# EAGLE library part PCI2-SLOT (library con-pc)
PCI BOARD SHORT

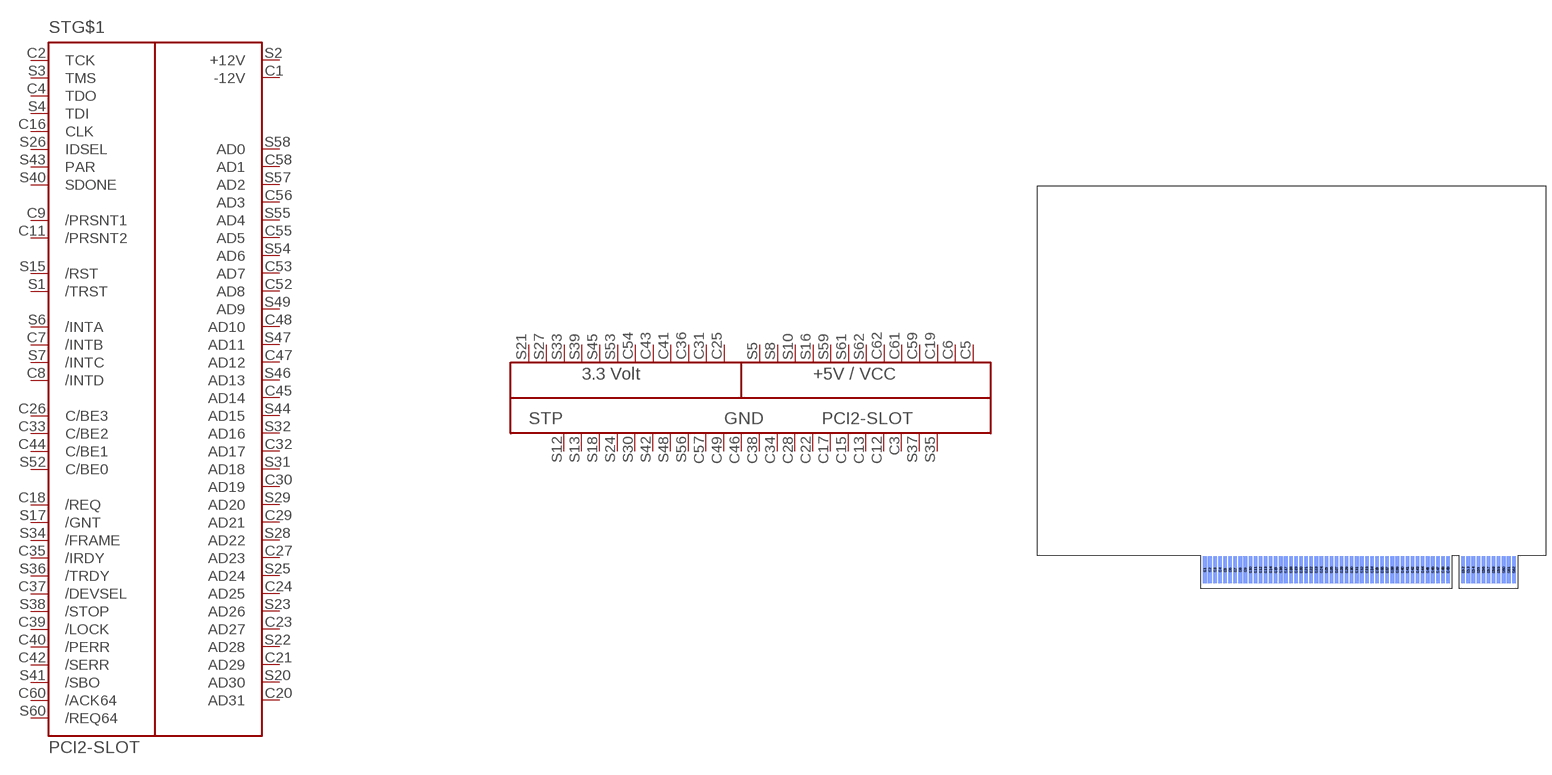
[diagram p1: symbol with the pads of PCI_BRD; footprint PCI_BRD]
Designator prefix ST; gates G$1=PCI2_CON P=PCI_PWR

## PCI2-SLOT  [PCI_BRD]
C1  G$1:-12V  pwr
C2  G$1:TCK  pas
C3  P:GND  pwr
C4  G$1:TDO  pas
C5  P:+5V  pwr
C6  P:+5V  pwr
C7  G$1:/INTB  pas
C8  G$1:/INTD  pas
C9  G$1:/PRSNT1  pas
C10  P:NC3  nc
C11  G$1:/PRSNT2  pas
C12  P:GND  pwr
C13  P:GND  pwr
C14  P:NC4  nc
C15  P:GND  pwr
C16  G$1:CLK  pas
C17  P:GND  pwr
C18  G$1:/REQ  pas
C19  P:+5V  pwr
C20  G$1:AD31  pas
C21  G$1:AD29  pas
C22  P:GND  pwr
C23  G$1:AD27  pas
C24  G$1:AD25  pas
C25  P:+3,3V  pwr
C26  G$1:C/BE3  pas
C27  G$1:AD23  pas
C28  P:GND  pwr
C29  G$1:AD21  pas
C30  G$1:AD19  pas
C31  P:+3,3V  pwr
C32  G$1:AD17  pas
C33  G$1:C/BE2  pas
C34  P:GND  pwr
C35  G$1:/IRDY  pas
C36  P:+3,3V  pwr
C37  G$1:/DEVSEL  pas
C38  P:GND  pwr
C39  G$1:/LOCK  pas
C40  G$1:/PERR  pas
C41  P:+3,3V  pwr
C42  G$1:/SERR  pas
C43  P:+3,3V  pwr
C44  G$1:C/BE1  pas
C45  G$1:AD14  pas
C46  P:GND  pwr
C47  G$1:AD12  pas
C48  G$1:AD10  pas
C49  P:GND  pwr
C52  G$1:AD8  pas
C53  G$1:AD7  pas
C54  P:+3,3V  pwr
C55  G$1:AD5  pas
C56  G$1:AD3  pas
C57  P:GND  pwr
C58  G$1:AD1  pas
C59  P:+5V  pwr
C60  G$1:/ACK64  pas
C61  P:+5V  pwr
C62  P:+5V  pwr
S1  G$1:/TRST  pas
S2  G$1:+12V  pwr
S3  G$1:TMS  pas
S4  G$1:TDI  pas
S5  P:+5V  pwr
S6  G$1:/INTA  pas
S7  G$1:/INTC  pas
S8  P:+5V  pwr
S9  P:NC0  nc
S10  P:+5V  pwr
S11  P:NC5  nc
S12  P:GND  pwr
S13  P:GND  pwr
S14  P:NC1  nc
S15  G$1:/RST  pas
S16  P:+5V  pwr
S17  G$1:/GNT  pas
S18  P:GND  pwr
S19  P:NC2  nc
S20  G$1:AD30  pas
S21  P:+3,3V  pwr
S22  G$1:AD28  pas
S23  G$1:AD26  pas
S24  P:GND  pwr
S25  G$1:AD24  pas
S26  G$1:IDSEL  pas
S27  P:+3,3V  pwr
S28  G$1:AD22  pas
S29  G$1:AD20  pas
S30  P:GND  pwr
S31  G$1:AD18  pas
S32  G$1:AD16  pas
S33  P:+3,3V  pwr
S34  G$1:/FRAME  pas
S35  P:GND  pas
S36  G$1:/TRDY  pas
S37  P:GND  pwr
S38  G$1:/STOP  pas
S39  P:+3,3V  pas
S40  G$1:SDONE  pas
S41  G$1:/SBO  pas
S42  P:GND  pwr
S43  G$1:PAR  pas
S44  G$1:AD15  pas
S45  P:+3,3V  pwr
S46  G$1:AD13  pas
S47  G$1:AD11  pas
S48  P:GND  pwr
S49  G$1:AD9  pas
S52  G$1:C/BE0  pas
S53  P:+3,3V  pwr
S54  G$1:AD6  pas
S55  G$1:AD4  pas
S56  P:GND  pwr
S57  G$1:AD2  pas
S58  G$1:AD0  pas
S59  P:+5V  pwr
S60  G$1:/REQ64  pas
S61  P:+5V  pwr
S62  P:+5V  pwr

## Footprint PCI_BRD (pad centres in mm)
PCI BOARD SHORT
smd 0.91 x 6.7: C1 41.91,4.763; C2 43.18,4.763; C3 44.45,4.763; C4 45.72,4.763; C5 46.99,4.763; C6 48.26,4.763; C7 49.53,4.763; C8 50.8,4.763; C9 52.07,4.763; C10 53.34,4.763; C11 54.61,4.763; C12 55.88,4.763; C13 57.15,4.763; C14 58.42,4.763; C15 59.69,4.763; C16 60.96,4.763; C17 62.23,4.763; C18 63.5,4.763; C19 64.77,4.763; C20 66.04,4.763; C21 67.31,4.763; C22 68.58,4.763; C23 69.85,4.763; C24 71.12,4.763; C25 72.39,4.763; C26 73.66,4.763; C27 74.93,4.763; C28 76.2,4.763; C29 77.47,4.763; C30 78.74,4.763; C31 80.01,4.763; C32 81.28,4.763; C33 82.55,4.763; C34 83.82,4.763; C35 85.09,4.763; C36 86.36,4.763; C37 87.63,4.763; C38 88.9,4.763; C39 90.17,4.763; C40 91.44,4.763; C41 92.71,4.763; C42 93.98,4.763; C43 95.25,4.763; C44 96.52,4.763; C45 97.79,4.763; C46 99.06,4.763; C47 100.33,4.763; C48 101.6,4.763; C49 102.87,4.763; C52 106.68,4.763; C53 107.95,4.763; C54 109.22,4.763; C55 110.49,4.763; C56 111.76,4.763; C57 113.03,4.763; C58 114.3,4.763; C59 115.57,4.763; C60 116.84,4.763; C61 118.11,4.763; C62 119.38,4.763
smd 0.91 x 6.7 bottom: S1 41.91,4.763; S2 43.18,4.763; S3 44.45,4.763; S4 45.72,4.763; S5 46.99,4.763; S6 48.26,4.763; S7 49.53,4.763; S8 50.8,4.763; S9 52.07,4.763; S10 53.34,4.763; S11 54.61,4.763; S12 55.88,4.763; S13 57.15,4.763; S14 58.42,4.763; S15 59.69,4.763; S16 60.96,4.763; S17 62.23,4.763; S18 63.5,4.763; S19 64.77,4.763; S20 66.04,4.763; S21 67.31,4.763; S22 68.58,4.763; S23 69.85,4.763; S24 71.12,4.763; S25 72.39,4.763; S26 73.66,4.763; S27 74.93,4.763; S28 76.2,4.763; S29 77.47,4.763; S30 78.74,4.763; S31 80.01,4.763; S32 81.28,4.763; S33 82.55,4.763; S34 83.82,4.763; S35 85.09,4.763; S36 86.36,4.763; S37 87.63,4.763; S38 88.9,4.763; S39 90.17,4.763; S40 91.44,4.763; S41 92.71,4.763; S42 93.98,4.763; S43 95.25,4.763; S44 96.52,4.763; S45 97.79,4.763; S46 99.06,4.763; S47 100.33,4.763; S48 101.6,4.763; S49 102.87,4.763; S52 106.68,4.763; S53 107.95,4.763; S54 109.22,4.763; S55 110.49,4.763; S56 111.76,4.763; S57 113.03,4.763; S58 114.3,4.763; S59 115.57,4.763; S60 116.84,4.763; S61 118.11,4.763; S62 119.38,4.763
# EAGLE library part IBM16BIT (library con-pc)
16-bit CARD IBM/PC-AT

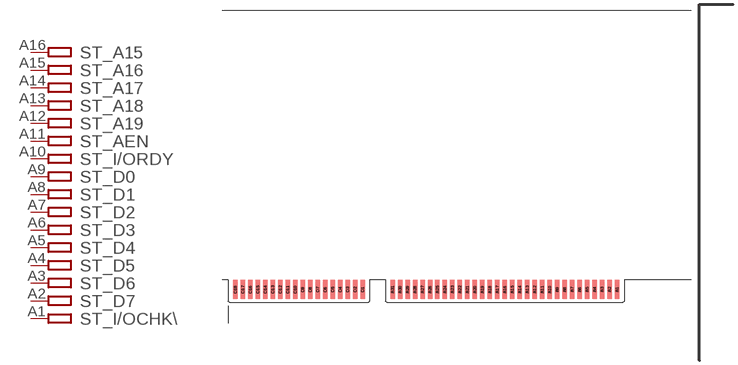
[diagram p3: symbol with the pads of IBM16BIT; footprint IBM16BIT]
Designator prefix ST; gates _I/OCHK\=ATPIN _D7=ATPIN _D6=ATPIN _D5=ATPIN _D4=ATPIN _D3=ATPIN _D2=ATPIN _D1=ATPIN _D0=ATPIN _I/ORDY=ATPIN _AEN=ATPIN _A19=ATPIN _A18=ATPIN _A17=ATPIN _A16=ATPIN _A15=ATPIN _A14=ATPIN _A13=ATPIN _A12=ATPIN _A11=ATPIN _A10=ATPIN _A9=ATPIN _A8=ATPIN _A7=ATPIN _A6=ATPIN _A5=ATPIN _A4=ATPIN _A3=ATPIN _A2=ATPIN _A1=ATPIN _A0=ATPIN _GND@3=ATPIN _RESET=ATPIN _+5V@2=ATPIN _IRQ9=ATPIN _-5V=ATPIN _DRQ2=ATPIN _-12V=ATPIN _CARDS=ATPIN _+12V=ATPIN _GND@2=ATPIN _MEMW\=ATPIN _MEMR\=ATPIN _IOW\=ATPIN _IOR\=ATPIN _DACK3\=ATPIN _DRQ3=ATPIN _DACK1\=ATPIN _DRQ1=ATPIN _REFRS=ATPIN _CLK=ATPIN _IRQ7=ATPIN _IRQ6=ATPIN _IRQ5=ATPIN _IRQ4=ATPIN _IRQ3=ATPIN _DACK2\=ATPIN _T/C=ATPIN _ALE=ATPIN _+5V@1=ATPIN _OSC=ATPIN _GND@1=ATPIN _SBHE=ATPIN _LA23=ATPIN _LA22=ATPIN _LA21=ATPIN _LA20=ATPIN _LA19=ATPIN _LA18=ATPIN _LA17=ATPIN _MEM_R=ATPIN _MEM_W=ATPIN _D8=ATPIN _D9=ATPIN _D10=ATPIN _D11=ATPIN _D12=ATPIN _D13=ATPIN _D14=ATPIN _D15=ATPIN _MEMCS16=ATPIN _I/OCS16=ATPIN _IRQ10=ATPIN _IRQ11=ATPIN _IRQ12=ATPIN _IRQ15=ATPIN _IRQ14=ATPIN _DACK0=ATPIN _DRQ0=ATPIN _DACK5=ATPIN _DRQ5=ATPIN _DACK6=ATPIN _DRQ6=ATPIN _DACK7=ATPIN _DRQ7=ATPIN _+5V@3=ATPIN _MASTER=ATPIN _GND@4=ATPIN

## IBM16BIT  [IBM16BIT]
A1  _I/OCHK\:P
A2  _D7:P
A3  _D6:P
A4  _D5:P
A5  _D4:P
A6  _D3:P
A7  _D2:P
A8  _D1:P
A9  _D0:P
A10  _I/ORDY:P
A11  _AEN:P
A12  _A19:P
A13  _A18:P
A14  _A17:P
A15  _A16:P
A16  _A15:P
A17  _A14:P
A18  _A13:P
A19  _A12:P
A20  _A11:P
A21  _A10:P
A22  _A9:P
A23  _A8:P
A24  _A7:P
A25  _A6:P
A26  _A5:P
A27  _A4:P
A28  _A3:P
A29  _A2:P
A30  _A1:P
A31  _A0:P
B1  _GND@3:P
B2  _RESET:P
B3  _+5V@2:P
B4  _IRQ9:P
B5  _-5V:P
B6  _DRQ2:P
B7  _-12V:P
B8  _CARDS:P
B9  _+12V:P
B10  _GND@2:P
B11  _MEMW\:P
B12  _MEMR\:P
B13  _IOW\:P
B14  _IOR\:P
B15  _DACK3\:P
B16  _DRQ3:P
B17  _DACK1\:P
B18  _DRQ1:P
B19  _REFRS:P
B20  _CLK:P
B21  _IRQ7:P
B22  _IRQ6:P
B23  _IRQ5:P
B24  _IRQ4:P
B25  _IRQ3:P
B26  _DACK2\:P
B27  _T/C:P
B28  _ALE:P
B29  _+5V@1:P
B30  _OSC:P
B31  _GND@1:P
C1  _SBHE:P
C2  _LA23:P
C3  _LA22:P
C4  _LA21:P
C5  _LA20:P
C6  _LA19:P
C7  _LA18:P
C8  _LA17:P
C9  _MEM_R:P
C10  _MEM_W:P
C11  _D8:P
C12  _D9:P
C13  _D10:P
C14  _D11:P
C15  _D12:P
C16  _D13:P
C17  _D14:P
C18  _D15:P
D1  _MEMCS16:P
D2  _I/OCS16:P
D3  _IRQ10:P
D4  _IRQ11:P
D5  _IRQ12:P
D6  _IRQ15:P
D7  _IRQ14:P
D8  _DACK0:P
D9  _DRQ0:P
D10  _DACK5:P
D11  _DRQ5:P
D12  _DACK6:P
D13  _DRQ6:P
D14  _DACK7:P
D15  _DRQ7:P
D16  _+5V@3:P
D17  _MASTER:P
D18  _GND@4:P

## Footprint IBM16BIT (pad centres in mm)
16-bit CARD IBM/PC-AT
smd 1.524 x 6.477: A1 -25.4,5.08; A2 -27.94,5.08; A3 -30.48,5.08; A4 -33.02,5.08; A5 -35.56,5.08; A6 -38.1,5.08; A7 -40.64,5.08; A8 -43.18,5.08; A9 -45.72,5.08; A10 -48.26,5.08; A11 -50.8,5.08; A12 -53.34,5.08; A13 -55.88,5.08; A14 -58.42,5.08; A15 -60.96,5.08; A16 -63.5,5.08; A17 -66.04,5.08; A18 -68.58,5.08; A19 -71.12,5.08; A20 -73.66,5.08; A21 -76.2,5.08; A22 -78.74,5.08; A23 -81.28,5.08; A24 -83.82,5.08; A25 -86.36,5.08; A26 -88.9,5.08; A27 -91.44,5.08; A28 -93.98,5.08; A29 -96.52,5.08; A30 -99.06,5.08; A31 -101.6,5.08; C1 -111.76,5.08; C2 -114.3,5.08; C3 -116.84,5.08; C4 -119.38,5.08; C5 -121.92,5.08; C6 -124.46,5.08; C7 -127,5.08; C8 -129.54,5.08; C9 -132.08,5.08; C10 -134.62,5.08; C11 -137.16,5.08; C12 -139.7,5.08; C13 -142.24,5.08; C14 -144.78,5.08; C15 -147.32,5.08; C16 -149.86,5.08; C17 -152.4,5.08; C18 -154.94,5.08
smd 1.524 x 6.477 bottom: B1 -25.4,5.08; B2 -27.94,5.08; B3 -30.48,5.08; B4 -33.02,5.08; B5 -35.56,5.08; B6 -38.1,5.08; B7 -40.64,5.08; B8 -43.18,5.08; B9 -45.72,5.08; B10 -48.26,5.08; B11 -50.8,5.08; B12 -53.34,5.08; B13 -55.88,5.08; B14 -58.42,5.08; B15 -60.96,5.08; B16 -63.5,5.08; B17 -66.04,5.08; B18 -68.58,5.08; B19 -71.12,5.08; B20 -73.66,5.08; B21 -76.2,5.08; B22 -78.74,5.08; B23 -81.28,5.08; B24 -83.82,5.08; B25 -86.36,5.08; B26 -88.9,5.08; B27 -91.44,5.08; B28 -93.98,5.08; B29 -96.52,5.08; B30 -99.06,5.08; B31 -101.6,5.08; D1 -111.76,5.08; D2 -114.3,5.08; D3 -116.84,5.08; D4 -119.38,5.08; D5 -121.92,5.08; D6 -124.46,5.08; D7 -127,5.08; D8 -129.54,5.08; D9 -132.08,5.08; D10 -134.62,5.08; D11 -137.16,5.08; D12 -139.7,5.08; D13 -142.24,5.08; D14 -144.78,5.08; D15 -147.32,5.08; D16 -149.86,5.08; D17 -152.4,5.08; D18 -154.94,5.08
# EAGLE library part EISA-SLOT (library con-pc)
EISA SLOT

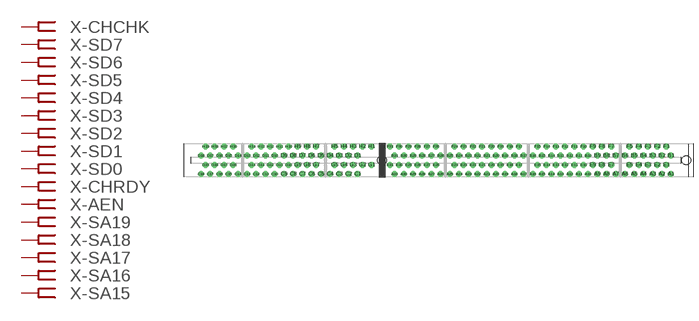
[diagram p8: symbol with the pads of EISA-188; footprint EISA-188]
Designator prefix X; gates -CHCHK=FEMREC -SD7=FEMREC -SD6=FEMREC -SD5=FEMREC -SD4=FEMREC -SD3=FEMREC -SD2=FEMREC -SD1=FEMREC -SD0=FEMREC -CHRDY=FEMREC -AEN=FEMREC -SA19=FEMREC -SA18=FEMREC -SA17=FEMREC -SA16=FEMREC -SA15=FEMREC -SA14=FEMREC -SA13=FEMREC -SA12=FEMREC -SA11=FEMREC -SA10=FEMREC -SA9=FEMREC -SA8=FEMREC -SA7=FEMREC -SA6=FEMREC -SA5=FEMREC -SA4=FEMREC -SA3=FEMREC -SA2=FEMREC -SA1=FEMREC -SA0=FEMREC GND11=GND -RESV10=FEMREC +5V5=+5V -IRQ2=FEMREC -5V0=-5V -DRQ2=FEMREC -12V0=-12V -NOWS=FEMREC +12V0=+12V GND12=GND -SMWTC=FEMREC -SMRDC=FEMREC -IOWC=FEMREC -IORC=FEMREC -DAK3=FEMREC -DRQ3=FEMREC -DAK1=FEMREC -DRQ1=FEMREC -REFRESH=FEMREC -BLCK=FEMREC -IRQ7=FEMREC -IRQ6=FEMREC -IRQ5=FEMREC -IRQ4=FEMREC -IRQ3=FEMREC -DAK2=FEMREC -TC=FEMREC -BALE=FEMREC +5V6=+5V -OSC=FEMREC GND13=GND -CMD=FEMREC -START=FEMREC -EXRDY=FEMREC -EX32=FEMREC GND0=GND -EX16=FEMREC -SLBURST=FEMREC -MSBURST=FEMREC -W/R=FEMREC GND1=GND -RESERV1=RESERV -RESERV2=RESERV -RESERV3=RESERV GND2=GND -BE1=FEMREC -LA31=FEMREC GND3=GND -LA30=FEMREC -LA28=FEMREC -LA27=FEMREC -LA25=FEMREC GND4=GND -LA15=FEMREC -LA13=FEMREC -LA12=FEMREC -LA11=FEMREC GND5=GND -LA9=FEMREC GND6=GND +5V0=+5V +5V1=+5V -RESERV4=RESERV -RESERV5=RESERV -RESERV6=RESERV -RESERV7=RESERV +12V=+12V -M/IO=FEMREC -LOCK=FEMREC -RESERV8=RESERV GND7=GND -RESERV9=RESERV -BE3=FEMREC -BE2=FEMREC -BE0=FEMREC GND8=GND +5V2=+5V -LA29=FEMREC GND9=GND -LA26=FEMREC -LA24=FEMREC -LA16=FEMREC -LA14=FEMREC +5V3=+5V +5V4=+5V GND10=GND -LA10=FEMREC -SBHE=FEMREC -LA23=FEMREC -LA22=FEMREC -LA21=FEMREC -LA20=FEMREC -LA19=FEMREC -LA18=FEMREC -LA17=FEMREC -MRDC=FEMREC -MWTC=FEMREC -SD8=FEMREC -SD9=FEMREC -SD10=FEMREC -SD11=FEMREC -SD12=FEMREC -SD13=FEMREC -SD14=FEMREC -SD15=FEMREC -M16=FEMREC -IO16=FEMREC -IRQ10=FEMREC -IRQ11=FEMREC -IRQ12=FEMREC -IRQ13=FEMREC -IRQ14=FEMREC -DAK0=FEMREC -DRQ0=FEMREC -DAK5=FEMREC -DRQ5=FEMREC -DAK6=FEMREC -DRQ6=FEMREC -DAK7=FEMREC -DRQ7=FEMREC +5V10=+5V MASTER16=FEMREC GND20=GND -LA7=FEMREC GND14=GND -LA4=FEMREC -LA3=FEMREC GND15=GND -SD17=FEMREC -SD19=FEMREC -SD20=FEMREC -SD22=FEMREC GND16=GND -SD25=FEMREC -SD26=FEMREC -SD28=FEMREC GND17=GND -SD30=FEMREC -SD31=FEMREC -MREQX=FEMREC -LA8=FEMREC -LA6=FEMREC -LA5=FEMREC +5V7=+5V -LA2=FEMREC -SD16=FEMREC -SD18=FEMREC GND18=GND -SD21=FEMREC -SD23=FEMREC -SD24=FEMREC GND19=GND -SD27=FEMREC -SD29=FEMREC +5V8=+5V +5V9=+5V -MAKX=FEMREC

## EISA-SLOT  [EISA-188]
A1  -CHCHK:P  pas
A2  -SD7:P  pas
A3  -SD6:P  pas
A4  -SD5:P  pas
A5  -SD4:P  pas
A6  -SD3:P  pas
A7  -SD2:P  pas
A8  -SD1:P  pas
A9  -SD0:P  pas
A10  -CHRDY:P  pas
A11  -AEN:P  pas
A12  -SA19:P  pas
A13  -SA18:P  pas
A14  -SA17:P  pas
A15  -SA16:P  pas
A16  -SA15:P  pas
A17  -SA14:P  pas
A18  -SA13:P  pas
A19  -SA12:P  pas
A20  -SA11:P  pas
A21  -SA10:P  pas
A22  -SA9:P  pas
A23  -SA8:P  pas
A24  -SA7:P  pas
A25  -SA6:P  pas
A26  -SA5:P  pas
A27  -SA4:P  pas
A28  -SA3:P  pas
A29  -SA2:P  pas
A30  -SA1:P  pas
A31  -SA0:P  pas
B1  GND11:GND  pwr
B2  -RESV10:P  pas
B3  +5V5:+5V  pwr
B4  -IRQ2:P  pas
B5  -5V0:-5V  pwr
B6  -DRQ2:P  pas
B7  -12V0:-12V  pwr
B8  -NOWS:P  pas
B9  +12V0:+12V  pwr
B10  GND12:GND  pwr
B11  -SMWTC:P  pas
B12  -SMRDC:P  pas
B13  -IOWC:P  pas
B14  -IORC:P  pas
B15  -DAK3:P  pas
B16  -DRQ3:P  pas
B17  -DAK1:P  pas
B18  -DRQ1:P  pas
B19  -REFRESH:P  pas
B20  -BLCK:P  pas
B21  -IRQ7:P  pas
B22  -IRQ6:P  pas
B23  -IRQ5:P  pas
B24  -IRQ4:P  pas
B25  -IRQ3:P  pas
B26  -DAK2:P  pas
B27  -TC:P  pas
B28  -BALE:P  pas
B29  +5V6:+5V  pwr
B30  -OSC:P  pas
B31  GND13:GND  pwr
C1  -SBHE:P  pas
C2  -LA23:P  pas
C3  -LA22:P  pas
C4  -LA21:P  pas
C5  -LA20:P  pas
C6  -LA19:P  pas
C7  -LA18:P  pas
C8  -LA17:P  pas
C9  -MRDC:P  pas
C10  -MWTC:P  pas
C11  -SD8:P  pas
C12  -SD9:P  pas
C13  -SD10:P  pas
C14  -SD11:P  pas
C15  -SD12:P  pas
C16  -SD13:P  pas
C17  -SD14:P  pas
C18  -SD15:P  pas
D1  -M16:P  pas
D2  -IO16:P  pas
D3  -IRQ10:P  pas
D4  -IRQ11:P  pas
D5  -IRQ12:P  pas
D6  -IRQ13:P  pas
D7  -IRQ14:P  pas
D8  -DAK0:P  pas
D9  -DRQ0:P  pas
D10  -DAK5:P  pas
D11  -DRQ5:P  pas
D12  -DAK6:P  pas
D13  -DRQ6:P  pas
D14  -DAK7:P  pas
D15  -DRQ7:P  pas
D16  +5V10:+5V  pwr
D17  MASTER16:P  pas
D18  GND20:GND  pwr
E1  -CMD:P  pas
E2  -START:P  pas
E3  -EXRDY:P  pas
E4  -EX32:P  pas
E5  GND0:GND  pwr
E7  -EX16:P  pas
E8  -SLBURST:P  pas
E9  -MSBURST:P  pas
E10  -W/R:P  pas
E11  GND1:GND  pwr
E12  -RESERV1:RSV  pas
E13  -RESERV2:RSV  pas
E14  -RESERV3:RSV  pas
E15  GND2:GND  pwr
E17  -BE1:P  pas
E18  -LA31:P  pas
E19  GND3:GND  pwr
E20  -LA30:P  pas
E21  -LA28:P  pas
E22  -LA27:P  pas
E23  -LA25:P  pas
E24  GND4:GND  pwr
E26  -LA15:P  pas
E27  -LA13:P  pas
E28  -LA12:P  pas
E29  -LA11:P  pas
E30  GND5:GND  pwr
E31  -LA9:P  pas
F1  GND6:GND  pwr
F2  +5V0:+5V  pwr
F3  +5V1:+5V  pwr
F4  -RESERV4:RSV  pas
F5  -RESERV5:RSV  pas
F7  -RESERV6:RSV  pas
F8  -RESERV7:RSV  pas
F9  +12V:+12V  pwr
F10  -M/IO:P  pas
F11  -LOCK:P  pas
F12  -RESERV8:RSV  pas
F13  GND7:GND  pwr
F14  -RESERV9:RSV  pas
F15  -BE3:P  pas
F17  -BE2:P  pas
F18  -BE0:P  pas
F19  GND8:GND  pwr
F20  +5V2:+5V  pwr
F21  -LA29:P  pas
F22  GND9:GND  pwr
F23  -LA26:P  pas
F24  -LA24:P  pas
F26  -LA16:P  pas
F27  -LA14:P  pas
F28  +5V3:+5V  pwr
F29  +5V4:+5V  pwr
F30  GND10:GND  pwr
F31  -LA10:P  pas
G1  -LA7:P  pas
G2  GND14:GND  pwr
G3  -LA4:P  pas
G4  -LA3:P  pas
G5  GND15:GND  pwr
G7  -SD17:P  pas
G8  -SD19:P  pas
G9  -SD20:P  pas
G10  -SD22:P  pas
G11  GND16:GND  pwr
G12  -SD25:P  pas
G13  -SD26:P  pas
G14  -SD28:P  pas
G16  GND17:GND  pwr
G17  -SD30:P  pas
G18  -SD31:P  pas
G19  -MREQX:P  pas
H1  -LA8:P  pas
H2  -LA6:P  pas
H3  -LA5:P  pas
H4  +5V7:+5V  pwr
H5  -LA2:P  pas
H7  -SD16:P  pas
H8  -SD18:P  pas
H9  GND18:GND  pwr
H10  -SD21:P  pas
H11  -SD23:P  pas
H12  -SD24:P  pas
H13  GND19:GND  pwr
H14  -SD27:P  pas
H16  -SD29:P  pas
H17  +5V8:+5V  pwr
H18  +5V9:+5V  pwr
H19  -MAKX:P  pas

## Footprint EISA-188 (pad centres in mm)
EISA SLOT
drill 1.1 pad 1.5 round: A1 79.65,-3.81; A2 77.11,-3.81; A3 74.57,-3.81; A4 72.03,-3.81; A5 69.49,-3.81; A6 66.95,-3.81; A7 64.41,-3.81; A8 61.87,-3.81; A9 59.33,-3.81; A10 56.79,-3.81; A11 54.25,-3.81; A12 51.71,-3.81; A13 49.17,-3.81; A14 46.63,-3.81; A15 44.09,-3.81; A16 41.55,-3.81; A17 39.01,-3.81; A18 36.47,-3.81; A19 33.93,-3.81; A20 31.39,-3.81; A21 28.85,-3.81; A22 26.31,-3.81; A23 23.77,-3.81; A24 21.23,-3.81; A25 18.69,-3.81; A26 16.15,-3.81; A27 13.61,-3.81; A28 11.07,-3.81; A29 8.53,-3.81; A30 5.99,-3.81; A31 3.45,-3.81; B1 79.65,1.27; B2 77.11,1.27; B3 74.57,1.27; B4 72.03,1.27; B5 69.49,1.27; B6 66.95,1.27; B7 64.41,1.27; B8 61.87,1.27; B9 59.33,1.27; B10 56.79,1.27; B11 54.25,1.27; B12 51.71,1.27; B13 49.17,1.27; B14 46.63,1.27; B15 44.09,1.27; B16 41.55,1.27; B17 39.01,1.27; B18 36.47,1.27; B19 33.93,1.27; B20 31.39,1.27; B21 28.85,1.27; B22 26.31,1.27; B23 23.77,1.27; B24 21.23,1.27; B25 18.69,1.27; B26 16.15,1.27; B27 13.61,1.27; B28 11.07,1.27; B29 8.53,1.27; B30 5.99,1.27; B31 3.45,1.27; C1 -6.71,-3.81; C2 -9.25,-3.81; C3 -11.79,-3.81; C4 -14.33,-3.81; C5 -16.87,-3.81; C6 -19.41,-3.81; C7 -21.95,-3.81; C8 -24.49,-3.81; C9 -27.03,-3.81; C10 -29.57,-3.81; C11 -32.11,-3.81; C12 -34.65,-3.81; C13 -37.19,-3.81; C14 -39.73,-3.81; C15 -42.27,-3.81; C16 -44.81,-3.81; C17 -47.35,-3.81; C18 -49.89,-3.81; D1 -6.71,1.27; D2 -9.25,1.27; D3 -11.79,1.27; D4 -14.33,1.27; D5 -16.87,1.27; D6 -19.41,1.27; D7 -21.95,1.27; D8 -24.49,1.27; D9 -27.03,1.27; D10 -29.57,1.27; D11 -32.11,1.27; D12 -34.65,1.27; D13 -37.19,1.27; D14 -39.73,1.27; D15 -42.27,1.27; D16 -44.81,1.27; D17 -47.35,1.27; D18 -49.89,1.27; E1 78.38,-1.27; E2 75.84,-1.27; E3 73.3,-1.27; E4 70.76,-1.27; E5 68.22,-1.27; E7 63.14,-1.27; E8 60.6,-1.27; E9 58.06,-1.27; E10 55.52,-1.27; E11 52.98,-1.27; E12 50.44,-1.27; E13 47.9,-1.27; E14 45.36,-1.27; E15 42.82,-1.27; E17 37.74,-1.27; E18 35.2,-1.27; E19 32.66,-1.27; E20 30.12,-1.27; E21 27.58,-1.27; E22 25.04,-1.27; E23 22.5,-1.27; E24 19.96,-1.27; E26 14.88,-1.27; E27 12.34,-1.27; E28 9.8,-1.27; E29 7.26,-1.27; E30 4.72,-1.27; E31 2.18,-1.27; F1 78.38,3.81; F2 75.84,3.81; F3 73.3,3.81; F4 70.76,3.81; F5 68.22,3.81; F7 63.14,3.81; F8 60.6,3.81; F9 58.06,3.81; F10 55.52,3.81; F11 52.98,3.81; F12 50.44,3.81; F13 47.9,3.81; F14 45.36,3.81; F15 42.82,3.81; F17 37.74,3.81; F18 35.2,3.81; F19 32.66,3.81; F20 30.12,3.81; F21 27.58,3.81; F22 25.04,3.81; F23 22.5,3.81; F24 19.96,3.81; F26 14.88,3.81; F27 12.34,3.81; F28 9.8,3.81; F29 7.26,3.81; F30 4.72,3.81; F31 2.18,3.81; G1 -2.9,-1.27; G2 -5.44,-1.27; G3 -7.98,-1.27; G4 -10.52,-1.27; G5 -13.06,-1.27; G7 -18.14,-1.27; G8 -20.68,-1.27; G9 -23.22,-1.27; G10 -25.76,-1.27; G11 -28.3,-1.27; G12 -30.84,-1.27; G13 -33.38,-1.27; G14 -35.92,-1.27; G16 -41,-1.27; G17 -43.54,-1.27; G18 -46.08,-1.27; G19 -48.62,-1.27; H1 -2.9,3.81; H2 -5.44,3.81; H3 -7.98,3.81; H4 -10.52,3.81; H5 -13.06,3.81; H7 -18.14,3.81; H8 -20.68,3.81; H9 -23.22,3.81; H10 -25.76,3.81; H11 -28.3,3.81; H12 -30.84,3.81; H13 -33.38,3.81; H14 -35.92,3.81; H16 -41,3.81; H17 -43.54,3.81; H18 -46.08,3.81; H19 -48.62,3.81
hole 2.44 at 83.86,0
hole 2.44 at 0,0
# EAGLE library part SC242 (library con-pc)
SLOT1 CONNECTOR Intel

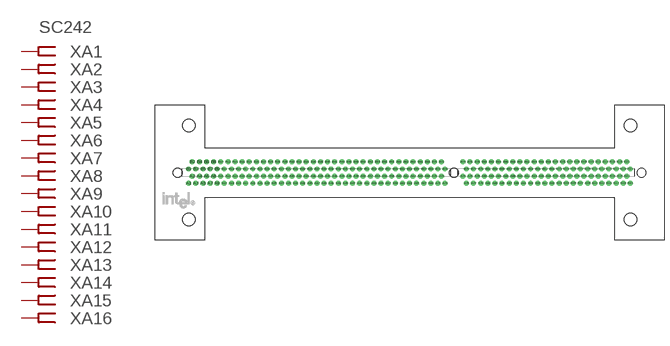
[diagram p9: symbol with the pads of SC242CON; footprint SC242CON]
Designator prefix X; gates A1=FEMRVAL A2=FEMREC A3=FEMREC A4=FEMREC A5=FEMREC A6=FEMREC A7=FEMREC A8=FEMREC A9=FEMREC A10=FEMREC A11=FEMREC A12=FEMREC A13=FEMREC A14=FEMREC A15=FEMREC A16=FEMREC A17=FEMREC A18=FEMREC A19=FEMREC A20=FEMREC A21=FEMREC A22=FEMREC A23=FEMREC A24=FEMREC A25=FEMREC A26=FEMREC A27=FEMREC A28=FEMREC A29=FEMREC A30=FEMREC A31=FEMREC A32=FEMREC A33=FEMREC A34=FEMREC A35=FEMREC A36=FEMREC A37=FEMREC A38=FEMREC A39=FEMREC A40=FEMREC A41=FEMREC A42=FEMREC A43=FEMREC A44=FEMREC A45=FEMREC A46=FEMREC A47=FEMREC A48=FEMREC A49=FEMREC A50=FEMREC A51=FEMREC A52=FEMREC A53=FEMREC A54=FEMREC A55=FEMREC A56=FEMREC A57=FEMREC A58=FEMREC A59=FEMREC A60=FEMREC A61=FEMREC A62=FEMREC A63=FEMREC A64=FEMREC A65=FEMREC A66=FEMREC A67=FEMREC A68=FEMREC A69=FEMREC A70=FEMREC A71=FEMREC A72=FEMREC A73=FEMREC A74=FEMREC A75=FEMREC A76=FEMREC A77=FEMREC A78=FEMREC A79=FEMREC A80=FEMREC A81=FEMREC A82=FEMREC A83=FEMREC A84=FEMREC A85=FEMREC A86=FEMREC A87=FEMREC A88=FEMREC A89=FEMREC A90=FEMREC A91=FEMREC A92=FEMREC A93=FEMREC A94=FEMREC A95=FEMREC A96=FEMREC A97=FEMREC A98=FEMREC A99=FEMREC A100=FEMREC A101=FEMREC A102=FEMREC A103=FEMREC A104=FEMREC A105=FEMREC A106=FEMREC A107=FEMREC A108=FEMREC A109=FEMREC A110=FEMREC A111=FEMREC A112=FEMREC A113=FEMREC A114=FEMREC A115=FEMREC A116=FEMREC A117=FEMREC A118=FEMREC A119=FEMREC A120=FEMREC A121=FEMREC B1=FEMRVAL B2=FEMREC B3=FEMREC B4=FEMREC B5=FEMREC B6=FEMREC B7=FEMREC B8=FEMREC B9=FEMREC B10=FEMREC B11=FEMREC B12=FEMREC B13=FEMREC B14=FEMREC B15=FEMREC B16=FEMREC B17=FEMREC B18=FEMREC B19=FEMREC B20=FEMREC B21=FEMREC B22=FEMREC B23=FEMREC B24=FEMREC B25=FEMREC B26=FEMREC B27=FEMREC B28=FEMREC B29=FEMREC B30=FEMREC B31=FEMREC B32=FEMREC B33=FEMREC B34=FEMREC B35=FEMREC B36=FEMREC B37=FEMREC B38=FEMREC B39=FEMREC B40=FEMREC B41=FEMREC B42=FEMREC B43=FEMREC B44=FEMREC B45=FEMREC B46=FEMREC B47=FEMREC B48=FEMREC B49=FEMREC B50=FEMREC B51=FEMREC B52=FEMREC B53=FEMREC B54=FEMREC B55=FEMREC B56=FEMREC B57=FEMREC B58=FEMREC B59=FEMREC B60=FEMREC B61=FEMREC B62=FEMREC B63=FEMREC B64=FEMREC B65=FEMREC B66=FEMREC B67=FEMREC B68=FEMREC B69=FEMREC B70=FEMREC B71=FEMREC B72=FEMREC B73=FEMREC B74=FEMREC B75=FEMREC B76=FEMREC B77=FEMREC B78=FEMREC B79=FEMREC B80=FEMREC B81=FEMREC B82=FEMREC B83=FEMREC B84=FEMREC B85=FEMREC B86=FEMREC B87=FEMREC B88=FEMREC B89=FEMREC B90=FEMREC B91=FEMREC B92=FEMREC B93=FEMREC B94=FEMREC B95=FEMREC B96=FEMREC B97=FEMREC B98=FEMREC B99=FEMREC B100=FEMREC B101=FEMREC B102=FEMREC B103=FEMREC B104=FEMREC B105=FEMREC B106=FEMREC B107=FEMREC B108=FEMREC B109=FEMREC B110=FEMREC B111=FEMREC B112=FEMREC B113=FEMREC B114=FEMREC B115=FEMREC B116=FEMREC B117=FEMREC B118=FEMREC B119=FEMREC B120=FEMREC B121=FEMREC

## SC242  [SC242CON]
A1  A1:P  pas
A2  A2:P  pas
A3  A3:P  pas
A4  A4:P  pas
A5  A5:P  pas
A6  A6:P  pas
A7  A7:P  pas
A8  A8:P  pas
A9  A9:P  pas
A10  A10:P  pas
A11  A11:P  pas
A12  A12:P  pas
A13  A13:P  pas
A14  A14:P  pas
A15  A15:P  pas
A16  A16:P  pas
A17  A17:P  pas
A18  A18:P  pas
A19  A19:P  pas
A20  A20:P  pas
A21  A21:P  pas
A22  A22:P  pas
A23  A23:P  pas
A24  A24:P  pas
A25  A25:P  pas
A26  A26:P  pas
A27  A27:P  pas
A28  A28:P  pas
A29  A29:P  pas
A30  A30:P  pas
A31  A31:P  pas
A32  A32:P  pas
A33  A33:P  pas
A34  A34:P  pas
A35  A35:P  pas
A36  A36:P  pas
A37  A37:P  pas
A38  A38:P  pas
A39  A39:P  pas
A40  A40:P  pas
A41  A41:P  pas
A42  A42:P  pas
A43  A43:P  pas
A44  A44:P  pas
A45  A45:P  pas
A46  A46:P  pas
A47  A47:P  pas
A48  A48:P  pas
A49  A49:P  pas
A50  A50:P  pas
A51  A51:P  pas
A52  A52:P  pas
A53  A53:P  pas
A54  A54:P  pas
A55  A55:P  pas
A56  A56:P  pas
A57  A57:P  pas
A58  A58:P  pas
A59  A59:P  pas
A60  A60:P  pas
A61  A61:P  pas
A62  A62:P  pas
A63  A63:P  pas
A64  A64:P  pas
A65  A65:P  pas
A66  A66:P  pas
A67  A67:P  pas
A68  A68:P  pas
A69  A69:P  pas
A70  A70:P  pas
A71  A71:P  pas
A72  A72:P  pas
A73  A73:P  pas
A74  A74:P  pas
A75  A75:P  pas
A76  A76:P  pas
A77  A77:P  pas
A78  A78:P  pas
A79  A79:P  pas
A80  A80:P  pas
A81  A81:P  pas
A82  A82:P  pas
A83  A83:P  pas
A84  A84:P  pas
A85  A85:P  pas
A86  A86:P  pas
A87  A87:P  pas
A88  A88:P  pas
A89  A89:P  pas
A90  A90:P  pas
A91  A91:P  pas
A92  A92:P  pas
A93  A93:P  pas
A94  A94:P  pas
A95  A95:P  pas
A96  A96:P  pas
A97  A97:P  pas
A98  A98:P  pas
A99  A99:P  pas
A100  A100:P  pas
A101  A101:P  pas
A102  A102:P  pas
A103  A103:P  pas
A104  A104:P  pas
A105  A105:P  pas
A106  A106:P  pas
A107  A107:P  pas
A108  A108:P  pas
A109  A109:P  pas
A110  A110:P  pas
A111  A111:P  pas
A112  A112:P  pas
A113  A113:P  pas
A114  A114:P  pas
A115  A115:P  pas
A116  A116:P  pas
A117  A117:P  pas
A118  A118:P  pas
A119  A119:P  pas
A120  A120:P  pas
A121  A121:P  pas
B1  B1:P  pas
B2  B2:P  pas
B3  B3:P  pas
B4  B4:P  pas
B5  B5:P  pas
B6  B6:P  pas
B7  B7:P  pas
B8  B8:P  pas
B9  B9:P  pas
B10  B10:P  pas
B11  B11:P  pas
B12  B12:P  pas
B13  B13:P  pas
B14  B14:P  pas
B15  B15:P  pas
B16  B16:P  pas
B17  B17:P  pas
B18  B18:P  pas
B19  B19:P  pas
B20  B20:P  pas
B21  B21:P  pas
B22  B22:P  pas
B23  B23:P  pas
B24  B24:P  pas
B25  B25:P  pas
B26  B26:P  pas
B27  B27:P  pas
B28  B28:P  pas
B29  B29:P  pas
B30  B30:P  pas
B31  B31:P  pas
B32  B32:P  pas
B33  B33:P  pas
B34  B34:P  pas
B35  B35:P  pas
B36  B36:P  pas
B37  B37:P  pas
B38  B38:P  pas
B39  B39:P  pas
B40  B40:P  pas
B41  B41:P  pas
B42  B42:P  pas
B43  B43:P  pas
B44  B44:P  pas
B45  B45:P  pas
B46  B46:P  pas
B47  B47:P  pas
B48  B48:P  pas
B49  B49:P  pas
B50  B50:P  pas
B51  B51:P  pas
B52  B52:P  pas
B53  B53:P  pas
B54  B54:P  pas
B55  B55:P  pas
B56  B56:P  pas
B57  B57:P  pas
B58  B58:P  pas
B59  B59:P  pas
B60  B60:P  pas
B61  B61:P  pas
B62  B62:P  pas
B63  B63:P  pas
B64  B64:P  pas
B65  B65:P  pas
B66  B66:P  pas
B67  B67:P  pas
B68  B68:P  pas
B69  B69:P  pas
B70  B70:P  pas
B71  B71:P  pas
B72  B72:P  pas
B73  B73:P  pas
B74  B74:P  pas
B75  B75:P  pas
B76  B76:P  pas
B77  B77:P  pas
B78  B78:P  pas
B79  B79:P  pas
B80  B80:P  pas
B81  B81:P  pas
B82  B82:P  pas
B83  B83:P  pas
B84  B84:P  pas
B85  B85:P  pas
B86  B86:P  pas
B87  B87:P  pas
B88  B88:P  pas
B89  B89:P  pas
B90  B90:P  pas
B91  B91:P  pas
B92  B92:P  pas
B93  B93:P  pas
B94  B94:P  pas
B95  B95:P  pas
B96  B96:P  pas
B97  B97:P  pas
B98  B98:P  pas
B99  B99:P  pas
B100  B100:P  pas
B101  B101:P  pas
B102  B102:P  pas
B103  B103:P  pas
B104  B104:P  pas
B105  B105:P  pas
B106  B106:P  pas
B107  B107:P  pas
B108  B108:P  pas
B109  B109:P  pas
B110  B110:P  pas
B111  B111:P  pas
B112  B112:P  pas
B113  B113:P  pas
B114  B114:P  pas
B115  B115:P  pas
B116  B116:P  pas
B117  B117:P  pas
B118  B118:P  pas
B119  B119:P  pas
B120  B120:P  pas
B121  B121:P  pas

## Footprint SC242CON (pad centres in mm)
SLOT1 CONNECTOR Intel
drill 0.8 pad 1.4 round: A1 -74.5,-3; A2 -73.5,-1; A3 -72.5,-3; A4 -71.5,-1; A5 -70.5,-3; A6 -69.5,-1; A7 -68.5,-3; A8 -67.5,-1; A9 -66.5,-3; A10 -65.5,-1; A11 -64.5,-3; A12 -63.5,-1; A13 -62.5,-3; A14 -61.5,-1; A15 -60.5,-3; A16 -59.5,-1; A17 -58.5,-3; A18 -57.5,-1; A19 -56.5,-3; A20 -55.5,-1; A21 -54.5,-3; A22 -53.5,-1; A23 -52.5,-3; A24 -51.5,-1; A25 -50.5,-3; A26 -49.5,-1; A27 -48.5,-3; A28 -47.5,-1; A29 -46.5,-3; A30 -45.5,-1; A31 -44.5,-3; A32 -43.5,-1; A33 -42.5,-3; A34 -41.5,-1; A35 -40.5,-3; A36 -39.5,-1; A37 -38.5,-3; A38 -37.5,-1; A39 -36.5,-3; A40 -35.5,-1; A41 -34.5,-3; A42 -33.5,-1; A43 -32.5,-3; A44 -31.5,-1; A45 -30.5,-3; A46 -29.5,-1; A47 -28.5,-3; A48 -27.5,-1; A49 -26.5,-3; A50 -25.5,-1; A51 -24.5,-3; A52 -23.5,-1; A53 -22.5,-3; A54 -21.5,-1; A55 -20.5,-3; A56 -19.5,-1; A57 -18.5,-3; A58 -17.5,-1; A59 -16.5,-3; A60 -15.5,-1; A61 -14.5,-3; A62 -13.5,-1; A63 -12.5,-3; A64 -11.5,-1; A65 -10.5,-3; A66 -9.5,-1; A67 -8.5,-3; A68 -7.5,-1; A69 -6.5,-3; A70 -5.5,-1; A71 -4.5,-3; A72 -3.5,-1; A73 -2.5,-3; A74 2.5,-1; A75 3.5,-3; A76 4.5,-1; A77 5.5,-3; A78 6.5,-1; A79 7.5,-3; A80 8.5,-1; A81 9.5,-3; A82 10.5,-1; A83 11.5,-3; A84 12.5,-1; A85 13.5,-3; A86 14.5,-1; A87 15.5,-3; A88 16.5,-1; A89 17.5,-3; A90 18.5,-1; A91 19.5,-3; A92 20.5,-1; A93 21.5,-3; A94 22.5,-1; A95 23.5,-3; A96 24.5,-1; A97 25.5,-3; A98 26.5,-1; A99 27.5,-3; A100 28.5,-1; A101 29.5,-3; A102 30.5,-1; A103 31.5,-3; A104 32.5,-1; A105 33.5,-3; A106 34.5,-1; A107 35.5,-3; A108 36.5,-1; A109 37.5,-3; A110 38.5,-1; A111 39.5,-3; A112 40.5,-1; A113 41.5,-3; A114 42.5,-1; A115 43.5,-3; A116 44.5,-1; A117 45.5,-3; A118 46.5,-1; A119 47.5,-3; A120 48.5,-1; A121 49.5,-3; B1 -74.5,1; B2 -73.5,3; B3 -72.5,1; B4 -71.5,3; B5 -70.5,1; B6 -69.5,3; B7 -68.5,1; B8 -67.5,3; B9 -66.5,1; B10 -65.5,3; B11 -64.5,1; B12 -63.5,3; B13 -62.5,1; B14 -61.5,3; B15 -60.5,1; B16 -59.5,3; B17 -58.5,1; B18 -57.5,3; B19 -56.5,1; B20 -55.5,3; B21 -54.5,1; B22 -53.5,3; B23 -52.5,1; B24 -51.5,3; B25 -50.5,1; B26 -49.5,3; B27 -48.5,1; B28 -47.5,3; B29 -46.5,1; B30 -45.5,3; B31 -44.5,1; B32 -43.5,3; B33 -42.5,1; B34 -41.5,3; B35 -40.5,1; B36 -39.5,3; B37 -38.5,1; B38 -37.5,3; B39 -36.5,1; B40 -35.5,3; B41 -34.5,1; B42 -33.5,3; B43 -32.5,1; B44 -31.5,3; B45 -30.5,1; B46 -29.5,3; B47 -28.5,1; B48 -27.5,3; B49 -26.5,1; B50 -25.5,3; B51 -24.5,1; B52 -23.5,3; B53 -22.5,1; B54 -21.5,3; B55 -20.5,1; B56 -19.5,3; B57 -18.5,1; B58 -17.5,3; B59 -16.5,1; B60 -15.5,3; B61 -14.5,1; B62 -13.5,3; B63 -12.5,1; B64 -11.5,3; B65 -10.5,1; B66 -9.5,3; B67 -8.5,1; B68 -7.5,3; B69 -6.5,1; B70 -5.5,3; B71 -4.5,1; B72 -3.5,3; B73 -2.5,1; B74 2.5,3; B75 3.5,1; B76 4.5,3; B77 5.5,1; B78 6.5,3; B79 7.5,1; B80 8.5,3; B81 9.5,1; B82 10.5,3; B83 11.5,1; B84 12.5,3; B85 13.5,1; B86 14.5,3; B87 15.5,1; B88 16.5,3; B89 17.5,1; B90 18.5,3; B91 19.5,1; B92 20.5,3; B93 21.5,1; B94 22.5,3; B95 23.5,1; B96 24.5,3; B97 25.5,1; B98 26.5,3; B99 27.5,1; B100 28.5,3; B101 29.5,1; B102 30.5,3; B103 31.5,1; B104 32.5,3; B105 33.5,1; B106 34.5,3; B107 35.5,1; B108 36.5,3; B109 37.5,1; B110 38.5,3; B111 39.5,1; B112 40.5,3; B113 41.5,1; B114 42.5,3; B115 43.5,1; B116 44.5,3; B117 45.5,1; B118 46.5,3; B119 47.5,1; B120 48.5,3; B121 49.5,1
hole 2.5 at 0,0
hole 2.5 at 52.64,0
hole 2.5 at -77.64,0
hole 3.56 at -74.46,-13.17
hole 3.56 at -74.46,13.17
hole 3.56 at 49.52,-13.17
hole 3.56 at 49.52,13.17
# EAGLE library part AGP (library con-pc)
AGP Slot AMP connctor 145263 >PCT-GF40< 124 Position 1mm, card edge connector Drawing No: C-145263 Source: http://ecommas.tycoelectronics.com .. ENG_CD_145263_H.pdf

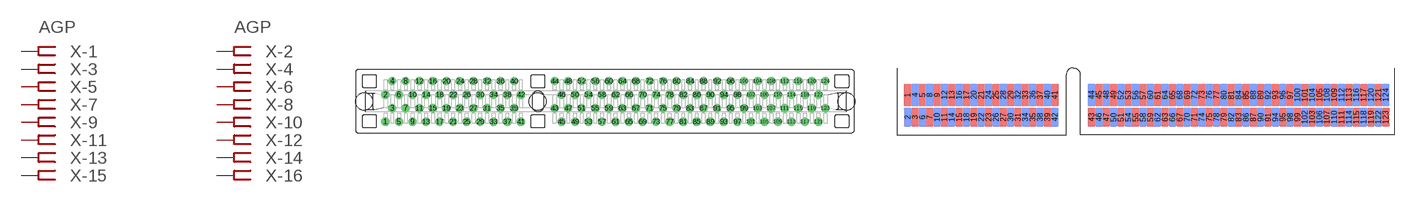
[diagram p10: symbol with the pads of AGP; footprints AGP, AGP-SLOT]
Designator prefix X; gates -1=FEMRVAL -2=FEMRVAL -3=FEMREC -4=FEMREC -5=FEMREC -6=FEMREC -7=FEMREC -8=FEMREC -9=FEMREC -10=FEMREC -11=FEMREC -12=FEMREC -13=FEMREC -14=FEMREC -15=FEMREC -16=FEMREC -17=FEMREC -18=FEMREC -19=FEMREC -20=FEMREC -21=FEMREC -22=FEMREC -23=FEMREC -24=FEMREC -25=FEMREC -26=FEMREC -27=FEMREC -28=FEMREC -29=FEMREC -30=FEMREC -31=FEMREC -32=FEMREC -33=FEMREC -34=FEMREC -35=FEMREC -36=FEMREC -37=FEMREC -38=FEMREC -39=FEMREC -40=FEMREC -41=FEMREC -42=FEMREC -43=FEMREC -44=FEMREC -45=FEMREC -46=FEMREC -47=FEMREC -48=FEMREC -49=FEMREC -50=FEMREC -51=FEMREC -52=FEMREC -53=FEMREC -54=FEMREC -55=FEMREC -56=FEMREC -57=FEMREC -58=FEMREC -59=FEMREC -60=FEMREC -61=FEMREC -62=FEMREC -63=FEMREC -64=FEMREC -65=FEMREC -66=FEMREC -67=FEMREC -68=FEMREC -69=FEMREC -70=FEMREC -71=FEMREC -72=FEMREC -73=FEMREC -74=FEMREC -75=FEMREC -76=FEMREC -77=FEMREC -78=FEMREC -79=FEMREC -80=FEMREC -81=FEMREC -82=FEMREC -83=FEMREC -84=FEMREC -85=FEMREC -86=FEMREC -87=FEMREC -88=FEMREC -89=FEMREC -90=FEMREC -91=FEMREC -92=FEMREC -93=FEMREC -94=FEMREC -95=FEMREC -96=FEMREC -97=FEMREC -98=FEMREC -99=FEMREC -100=FEMREC -101=FEMREC -102=FEMREC -103=FEMREC -104=FEMREC -105=FEMREC -106=FEMREC -107=FEMREC -108=FEMREC -109=FEMREC -110=FEMREC -111=FEMREC -112=FEMREC -113=FEMREC -114=FEMREC -115=FEMREC -116=FEMREC -117=FEMREC -118=FEMREC -119=FEMREC -120=FEMREC -121=FEMREC -122=FEMREC -123=FEMREC -124=FEMREC

## AGP  [AGP]
1  -1:P  pas
2  -2:P  pas
3  -3:P  pas
4  -4:P  pas
5  -5:P  pas
6  -6:P  pas
7  -7:P  pas
8  -8:P  pas
9  -9:P  pas
10  -10:P  pas
11  -11:P  pas
12  -12:P  pas
13  -13:P  pas
14  -14:P  pas
15  -15:P  pas
16  -16:P  pas
17  -17:P  pas
18  -18:P  pas
19  -19:P  pas
20  -20:P  pas
21  -21:P  pas
22  -22:P  pas
23  -23:P  pas
24  -24:P  pas
25  -25:P  pas
26  -26:P  pas
27  -27:P  pas
28  -28:P  pas
29  -29:P  pas
30  -30:P  pas
31  -31:P  pas
32  -32:P  pas
33  -33:P  pas
34  -34:P  pas
35  -35:P  pas
36  -36:P  pas
37  -37:P  pas
38  -38:P  pas
39  -39:P  pas
40  -40:P  pas
41  -41:P  pas
42  -42:P  pas
43  -43:P  pas
44  -44:P  pas
45  -45:P  pas
46  -46:P  pas
47  -47:P  pas
48  -48:P  pas
49  -49:P  pas
50  -50:P  pas
51  -51:P  pas
52  -52:P  pas
53  -53:P  pas
54  -54:P  pas
55  -55:P  pas
56  -56:P  pas
57  -57:P  pas
58  -58:P  pas
59  -59:P  pas
60  -60:P  pas
61  -61:P  pas
62  -62:P  pas
63  -63:P  pas
64  -64:P  pas
65  -65:P  pas
66  -66:P  pas
67  -67:P  pas
68  -68:P  pas
69  -69:P  pas
70  -70:P  pas
71  -71:P  pas
72  -72:P  pas
73  -73:P  pas
74  -74:P  pas
75  -75:P  pas
76  -76:P  pas
77  -77:P  pas
78  -78:P  pas
79  -79:P  pas
80  -80:P  pas
81  -81:P  pas
82  -82:P  pas
83  -83:P  pas
84  -84:P  pas
85  -85:P  pas
86  -86:P  pas
87  -87:P  pas
88  -88:P  pas
89  -89:P  pas
90  -90:P  pas
91  -91:P  pas
92  -92:P  pas
93  -93:P  pas
94  -94:P  pas
95  -95:P  pas
96  -96:P  pas
97  -97:P  pas
98  -98:P  pas
99  -99:P  pas
100  -100:P  pas
101  -101:P  pas
102  -102:P  pas
103  -103:P  pas
104  -104:P  pas
105  -105:P  pas
106  -106:P  pas
107  -107:P  pas
108  -108:P  pas
109  -109:P  pas
110  -110:P  pas
111  -111:P  pas
112  -112:P  pas
113  -113:P  pas
114  -114:P  pas
115  -115:P  pas
116  -116:P  pas
117  -117:P  pas
118  -118:P  pas
119  -119:P  pas
120  -120:P  pas
121  -121:P  pas
122  -122:P  pas
123  -123:P  pas
124  -124:P  pas

## AGP-SLOT  [AGP-SLOT]
Pads as for AGP

## Footprint AGP (pad centres in mm)
AGP Slot AMP connctor 145263 >PCT-GF40< 124 Position 1mm, card edge connector Drawing No: C-145263 Source: http://ecommas.tycoelectronics.com .. ENG_CD_145263_H.pdf
drill 0.7 pad 1.1 round: 1 0,-3; 2 0,1; 3 1,-1; 4 1,3; 5 2,-3; 6 2,1; 7 3,-1; 8 3,3; 9 4,-3; 10 4,1; 11 5,-1; 12 5,3; 13 6,-3; 14 6,1; 15 7,-1; 16 7,3; 17 8,-3; 18 8,1; 19 9,-1; 20 9,3; 21 10,-3; 22 10,1; 23 11,-1; 24 11,3; 25 12,-3; 26 12,1; 27 13,-1; 28 13,3; 29 14,-3; 30 14,1; 31 15,-1; 32 15,3; 33 16,-3; 34 16,1; 35 17,-1; 36 17,3; 37 18,-3; 38 18,1; 39 19,-1; 40 19,3; 41 20,-3; 42 20,1; 43 25,-1; 44 25,3; 45 26,-3; 46 26,1; 47 27,-1; 48 27,3; 49 28,-3; 50 28,1; 51 29,-1; 52 29,3; 53 30,-3; 54 30,1; 55 31,-1; 56 31,3; 57 32,-3; 58 32,1; 59 33,-1; 60 33,3; 61 34,-3; 62 34,1; 63 35,-1; 64 35,3; 65 36,-3; 66 36,1; 67 37,-1; 68 37,3; 69 38,-3; 70 38,1; 71 39,-1; 72 39,3; 73 40,-3; 74 40,1; 75 41,-1; 76 41,3; 77 42,-3; 78 42,1; 79 43,-1; 80 43,3; 81 44,-3; 82 44,1; 83 45,-1; 84 45,3; 85 46,-3; 86 46,1; 87 47,-1; 88 47,3; 89 48,-3; 90 48,1; 91 49,-1; 92 49,3; 93 50,-3; 94 50,1; 95 51,-1; 96 51,3; 97 52,-3; 98 52,1; 99 53,-1; 100 53,3; 101 54,-3; 102 54,1; 103 55,-1; 104 55,3; 105 56,-3; 106 56,1; 107 57,-1; 108 57,3; 109 58,-3; 110 58,1; 111 59,-1; 112 59,3; 113 60,-3; 114 60,1; 115 61,-1; 116 61,3; 117 62,-3; 118 62,1; 119 63,-1; 120 63,3; 121 64,-3; 122 64,1; 123 65,-1; 124 65,3
hole 2.5 at 22.5,0
hole 2.5 at -3.14,0
hole 2.5 at 68.14,0

## Footprint AGP-SLOT (pad centres in mm)
AGP 124 Position 1mm Card Edge connector Drawing No: C-145263 Source: http://ecommas.tycoelectronics.com .. ENG_CD_145263_H.pdf
smd 1.09 x 3.09: 1 1.5,5.46; 5 3.5,5.46; 9 5.5,5.46; 13 7.5,5.46; 17 9.5,5.46; 21 11.5,5.46; 25 13.5,5.46; 29 15.5,5.46; 33 17.5,5.46; 37 19.5,5.46; 41 21.5,5.46; 45 27.5,5.46; 49 29.5,5.46; 53 31.5,5.46; 57 33.5,5.46; 61 35.5,5.46; 65 37.5,5.46; 69 39.5,5.46; 73 41.5,5.46; 77 43.5,5.46; 81 45.5,5.46; 85 47.5,5.46; 89 49.5,5.46; 93 51.5,5.46; 97 53.5,5.46; 101 55.5,5.46; 105 57.5,5.46; 109 59.5,5.46; 113 61.5,5.46; 117 63.5,5.46; 121 65.5,5.46
smd 1.09 x 2.56 bottom: 2 1.5,2.42; 6 3.5,2.42; 10 5.5,2.42; 14 7.5,2.42; 18 9.5,2.42; 22 11.5,2.42; 26 13.5,2.42; 30 15.5,2.42; 34 17.5,2.42; 38 19.5,2.42; 42 21.5,2.42; 46 27.5,2.42; 50 29.5,2.42; 54 31.5,2.42; 58 33.5,2.42; 62 35.5,2.42; 66 37.5,2.42; 70 39.5,2.42; 74 41.5,2.42; 78 43.5,2.42; 82 45.5,2.42; 86 47.5,2.42; 90 49.5,2.42; 94 51.5,2.42; 98 53.5,2.42; 102 55.5,2.42; 106 57.5,2.42; 110 59.5,2.42; 114 61.5,2.42; 118 63.5,2.42; 122 65.5,2.42
smd 1.09 x 2.56: 3 2.5,2.42; 7 4.5,2.42; 11 6.5,2.42; 15 8.5,2.42; 19 10.5,2.42; 23 12.5,2.42; 27 14.5,2.42; 31 16.5,2.42; 35 18.5,2.42; 39 20.5,2.42; 43 26.5,2.42; 47 28.5,2.42; 51 30.5,2.42; 55 32.5,2.42; 59 34.5,2.42; 63 36.5,2.42; 67 38.5,2.42; 71 40.5,2.42; 75 42.5,2.42; 79 44.5,2.42; 83 46.5,2.42; 87 48.5,2.42; 91 50.5,2.42; 95 52.5,2.42; 99 54.5,2.42; 103 56.5,2.42; 107 58.5,2.42; 111 60.5,2.42; 115 62.5,2.42; 119 64.5,2.42; 123 66.5,2.42
smd 1.09 x 3.09 bottom: 4 2.5,5.46; 8 4.5,5.46; 12 6.5,5.46; 16 8.5,5.46; 20 10.5,5.46; 24 12.5,5.46; 28 14.5,5.46; 32 16.5,5.46; 36 18.5,5.46; 40 20.5,5.46; 44 26.5,5.46; 48 28.5,5.46; 52 30.5,5.46; 56 32.5,5.46; 60 34.5,5.46; 64 36.5,5.46; 68 38.5,5.46; 72 40.5,5.46; 76 42.5,5.46; 80 44.5,5.46; 84 46.5,5.46; 88 48.5,5.46; 92 50.5,5.46; 96 52.5,5.46; 100 54.5,5.46; 104 56.5,5.46; 108 58.5,5.46; 112 60.5,5.46; 116 62.5,5.46; 120 64.5,5.46; 124 66.5,5.46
